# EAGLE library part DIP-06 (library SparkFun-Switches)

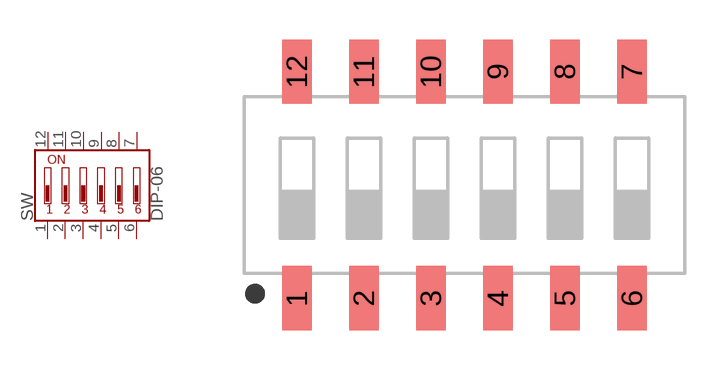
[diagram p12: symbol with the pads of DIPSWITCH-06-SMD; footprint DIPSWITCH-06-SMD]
Designator prefix SW

## DIP-06 (PROD_ID: SWCH-13756)  [DIPSWITCH-06-SMD]
1  1
2  2
3  3
4  4
5  5
6  6
7  7
8  8
9  9
10  10
11  11
12  12

## Footprint DIPSWITCH-06-SMD (pad centres in mm)
smd 1.13 x 2.44: 1 -6.35,-4.3; 2 -3.81,-4.3; 3 -1.27,-4.3; 4 1.27,-4.3; 5 3.81,-4.3; 6 6.35,-4.3; 7 6.35,4.3; 8 3.81,4.3; 9 1.27,4.3; 10 -1.27,4.3; 11 -3.81,4.3; 12 -6.35,4.3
